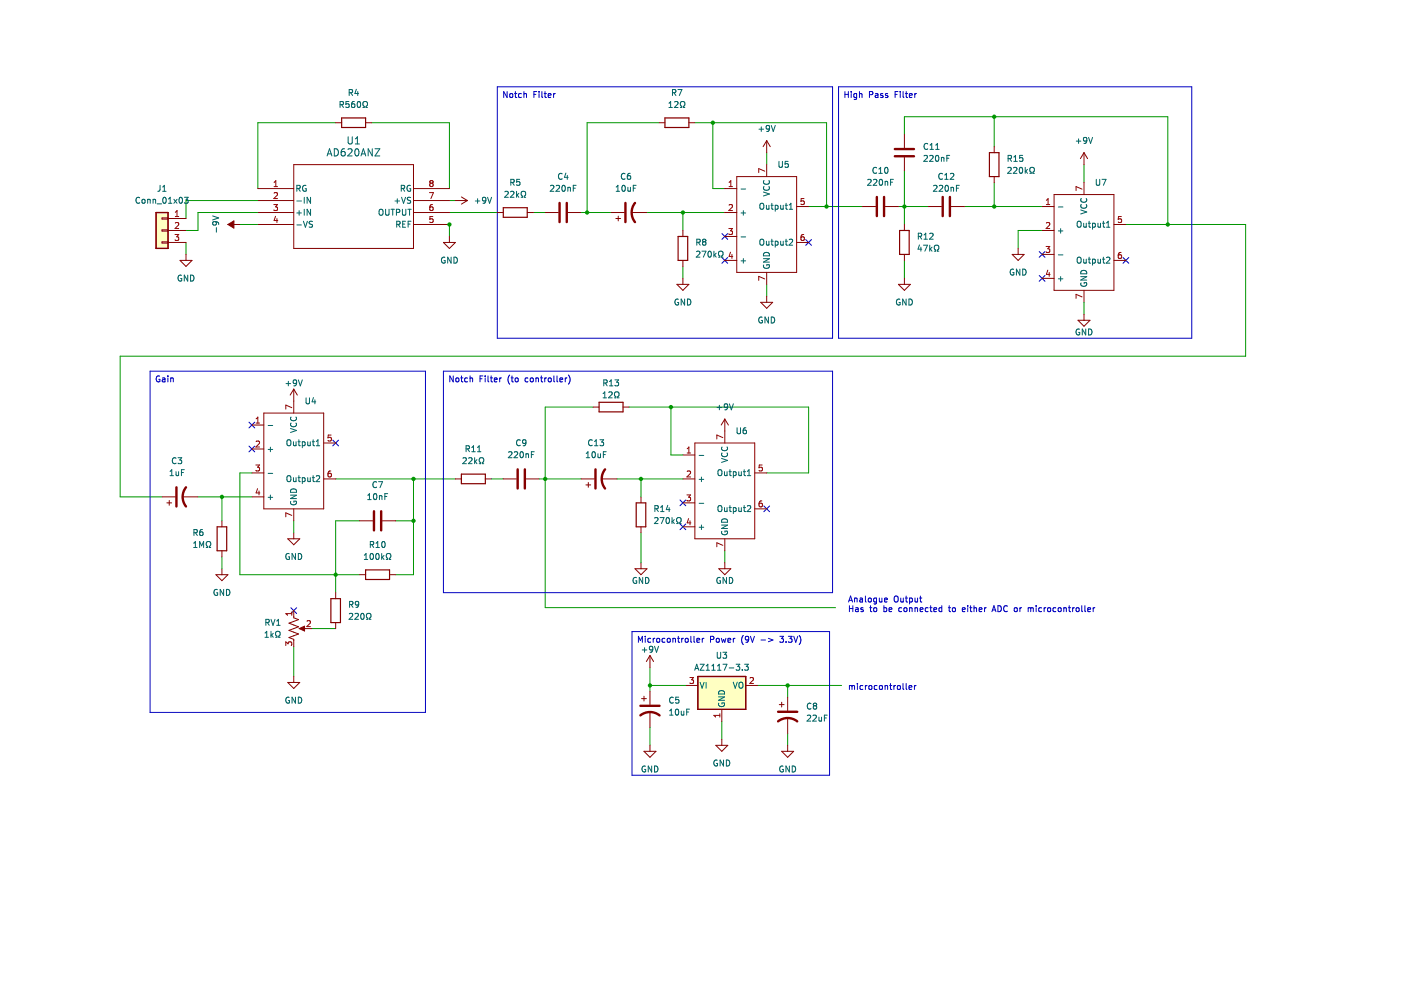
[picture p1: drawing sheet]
<svg xmlns="http://www.w3.org/2000/svg" width="297mm" height="210mm" viewBox="0 0 297 210" stroke-linecap="round" stroke-linejoin="round" font-family="sans-serif">
<path d="M148 143.4h10.1v7h-10.1z" fill-rule="evenodd" fill="#ffffc2"/>
<path d="M148 143.4h10.1v7h-10.1z" fill="none" stroke="#840000" stroke-width=".25"/>
<path d="M33.1 45.1h2.5v7.6h-2.5z" fill-rule="evenodd" fill="#ffffc2"/>
<path d="M141 25h5.1v2h-5.1zM33.1 45.1h2.5v7.6h-2.5zM106.7 44h5.1v2.1h-5.1zM143.8 50.1h2v5.1h-2zM127 85.3h5.1v2h-5.1zM46 111.7h2.1v5.1h-2.1zM134.9 106.6h2v5.1h-2zM70.2 126.9h2v5.1h-2zM77.5 120.8h5.1v2.1h-5.1zM148 143.4h10.1v7h-10.1z" fill="none" stroke="#840000" stroke-width=".25"/>
<g fill="none" stroke="#000084" stroke-width=".21">
<path d="M153.1 54.6l1.2 1.2M153.1 49.5l1.2 1.2M154.3 54.6l-1.2 1.2M154.3 49.5l-1.2 1.2M170.8 50.8l1.3 1.2M172.1 50.8l-1.3 1.2M220.3 53.3l1.3 1.3M220.3 58.4l1.3 1.2M221.6 53.3l-1.3 1.3M221.6 58.4l-1.3 1.2M238.1 54.6l1.2 1.2M239.3 54.6l-1.2 1.2"/>
<path d="M52.8 89.5l1.2 1.2M52.8 94.6l1.2 1.2M54 89.5l-1.2 1.2M54 94.6l-1.2 1.2M70.6 93.3l1.2 1.2M71.8 93.3l-1.2 1.2M144.2 106l1.2 1.2M144.2 111.1l1.2 1.2M145.4 106l-1.2 1.2M145.4 111.1l-1.2 1.2M161.9 107.3l1.3 1.2M163.2 107.3l-1.3 1.2"/>
<path d="M61.7 128.9l1.2 1.2M62.9 128.9l-1.2 1.2"/>
</g>
<g fill="none" stroke="#009600" stroke-width=".21">
<path d="M71.2 26h-16.5v14M78.8 26h16.5v14M139.7 26h-15.2v19.1M147.3 26h27.9v17.8M151.1 26v14h2.6M162.6 32.4v2.5M191.7 28.6v-3.8h55.9v22.8M191.7 36.2v11.4M210.8 24.8v6.3M210.8 38.7v5.1M229.8 34.9v3.8M39.4 51.4v2.5"/>
<path d="M50.9 47.6h3.8M54.7 45.1h-12.7v3.8h-2.6M54.7 42.5h-15.3v3.8M90.2 47.6h5.1v2.5M95.3 45.1h10.1M95.3 42.5h1.3M113.1 45.1h2.5M123.2 45.1h6.4M137.2 45.1h16.5M144.8 45.1v3.8M144.8 56.5v2.5M171.4 43.8h11.5"/>
<path d="M190.5 43.8h6.3M191.7 55.2v3.8M204.4 43.8h16.5M220.9 48.9h-5v3.8M238.7 47.6h25.4v27.9h-238.6v29.9h8.9M162.6 60.3v2.5M229.8 64.1v2.5M125.7 86.3h-10.1v42.5h61.6M133.4 86.3h38v14h-8.8M142.2 86.3v10.2h2.6M42 105.4h11.4M47.1 105.4v5"/>
<path d="M47.1 118v2.6M53.4 100.3h-2.5v21.6h25.3M62.3 110.4v2.6M71.2 101.5h25.4M76.2 110.4h-5v15.3M83.9 110.4h3.8M87.7 101.5v20.4h-3.8M104.2 101.5h2.5M114.3 101.5h8.9M130.8 101.5h14M135.9 101.5v3.9M135.9 113v6.3"/>
<path d="M153.7 116.8v2.5M62.3 137.1v6.3M66.1 133.3h5.1M137.8 145.3h7.6M137.8 141.5v5.1M137.8 154.2v3.8M153 152.9v3.9M160.7 145.3h17.7M167 145.3v2.6M167 155.5v2.5"/>
</g>
<g fill="none" stroke="#0000c2" stroke-width=".21">
<path d="M105.4 18.4h71.1v53.3h-71.1zM107.5 19.4v1.3l-.7-1.3v1.3M108.1 20l.2-.2 .4 .2-.1 .6h-.5zM109.1 19.8h.5M109.3 19.4v1.1l.3 .2M110.5 19.9l-.3-.1-.3 .3 .2 .5h.4M111.1 20l.5-.1v.8M111.1 19.4v1.3M113.8 19.4h-.6v1.3M114.3 19.4v.1M114.3 19.8v.9M114.9 19.4v1.1l.2 .2"/>
<path d="M115.4 19.8h.5M115.6 19.4v1.1l.3 .2M117.4 19.8v.9M117.7 19.8l-.3 .3M177.8 18.4h74.9v53.3h-74.9zM179.1 19.4v1.3M179.9 19.4v1.3M180.5 19.4v.1M180.5 19.8v.9M181.6 19.9l-.3-.1-.3 .3 .1 .5h.5M181.6 19.8v1.1l-.2 .2-.3-.1M182.2 20l.5-.1 .1 .8"/>
<path d="M182.2 19.4v1.3M185.6 19.9h.5l.1 .8M187.2 19.9l-.3-.1-.2 .2 .1 .2 .4 .1v.3h-.5M188.2 19.9l-.3-.1-.2 .2 .1 .2 .4 .1v.3h-.5M190.4 19.4h-.6v1.3M190.9 19.4v.1M190.9 19.8v.9M191.5 19.4v1.1l.2 .2M192 19.8h.4M192.1 19.4v1.1l.3 .2M194 19.8v.9M194.3 19.8l-.3 .3"/>
<path d="M113.2 20h.4M116.2 20.3l.6-.2v-.2l-.4-.1-.2 .2 .1 .6h.5M179.1 20h.8M184.3 20.1l.6-.1 .1-.5-.7-.1v1.3M186.2 20.1l-.7 .3 .2 .3 .5-.1M189.8 20h.4M192.8 20.3l.6-.2-.1-.2-.3-.1-.2 .2 .1 .6h.4M31.8 78.7h58.4v72.3h-58.4zM33.8 79.8a.58 .58 0 0 0-.7 .5 .58 .58 0 0 0 .8 .5v-.4h-.2M35.6 79.7v.1M94 78.7h82.5v47h-82.5zM96.1 79.7v1.3l-.7-1.3v1.3"/>
<path d="M97.8 79.7v1.1l.3 .2M99.7 79.7v1.3M102.4 79.7h-.6v1.3M102.9 79.7v.1M103.5 79.7v1.1l.1 .2M104.1 79.7v1.1l.3 .2M108.1 79.5a1.46 1.46 0 0 0 0 2M108.5 79.7v1.1l.3 .2M114.8 79.7v1.1l.3 .2M117.4 79.7v1.1l.2 .2M118.1 79.7v1.1l.2 .2M120.5 79.5a1.46 1.46 0 0 1 0 2"/>
<path d="M34.4 80.2h.5l.1 .8M35 80.4l-.6 .3 .2 .3 .4-.1M35.6 80.1v.9M36.2 80.2h.5v.8M36.2 80.1v.9M96.7 80.2l.2-.1 .3 .1v.7l-.5-.1zM97.7 80.1h.4M99.1 80.2l-.3-.1-.3 .3 .1 .5h.5M99.7 80.2h.4l.1 .8M101.8 80.3h.4M102.9 80.1v.9M104 80.1h.4"/>
<path d="M104.8 80.5l.6-.1-.1-.2-.3-.1-.2 .2 .1 .6h.4M105.9 80.1v.9M106.3 80.1l-.4 .3M108.4 80.1h.4M109.3 80.2l.2-.1 .3 .1v.7l-.5-.1zM111.9 80.2l-.3-.1-.3 .3 .1 .5h.5M112.5 80.2l.2-.1 .3 .1v.7l-.5-.1zM113.6 80.2h.5l.1 .8M113.6 80.1v.9M114.6 80.1h.5M115.5 80.1v.9M115.9 80.1l-.4 .3"/>
<path d="M116.3 80.2l.2-.1 .3 .1v.7l-.5-.1zM118.7 80.5l.6-.1-.1-.2-.3-.1-.2 .2 .1 .6h.4M119.8 80.1v.9M120.2 80.1l-.4 .3M134 133.9h41.9v30.5h-41.9zM135.4 136.2v-1.3l.4 .9 .4-.9v1.3M136.8 134.9v.1M136.8 135.3v.9M138 135.4l-.4-.1-.3 .3 .2 .5h.5M138.5 135.3v.9M138.9 135.3l-.4 .3M139.3 135.5l.2-.2 .3 .2v.6h-.5z"/>
<path d="M141 135.4l-.4-.1-.2 .3 .1 .5h.5M141.5 135.5l.2-.2 .4 .2-.1 .6h-.5zM142.7 135.5l.4-.1 .1 .8M142.7 135.3v.9M143.6 135.3h.5M143.8 134.9v1.1l.3 .2M144.5 135.3v.9M144.9 135.3l-.4 .3M145.3 135.5l.2-.2 .4 .2-.1 .6h-.5zM146.5 134.9v1.1l.2 .2M147.1 134.9v1.1l.2 .2M147.7 135.8l.6-.2v-.2l-.4-.1-.2 .2 .1 .6h.5"/>
<path d="M148.9 135.3v.9M149.3 135.3l-.4 .3M150.6 135.6l.6-.1 .1-.5-.7-.1v1.3M151.9 135.5l.2-.2 .4 .2-.1 .6h-.5zM152.9 135.3l.3 .9 .2-.6 .3 .6 .2-.9M154.3 135.8l.6-.2v-.2l-.4-.1-.2 .2 .1 .6h.5M155.5 135.3v.9M155.8 135.3l-.3 .3M157.6 134.7a1.46 1.46 0 0 0 0 2M158.7 135.5l-.2 .2-.4-.1v-.6l.4-.1 .2 .3v.7l-.2 .2-.4 .1M159.1 134.9l.4 1.3 .5-1.3M161.3 135.7h1"/>
<path d="M162.9 135.3l1 .4-1 .4M165.3 134.9h.8l-.4 .5 .4 .1v.6l-.2 .1-.6-.1M166.7 136.1v.1M167.1 134.9h.8l-.4 .5 .4 .1v.6l-.2 .1-.6-.1M168.3 134.9l.4 1.3 .4-1.3M169.4 134.7a1.46 1.46 0 0 1 0 2M179.9 127.6l.4-1.2 .5 1.2M180 127.3h.6M180.1 128.4v1.3M180.1 129h.7M180.8 128.4v1.3M181.2 126.8v.8"/>
<path d="M181.2 126.9h.5v.7M181.4 128.9h.5l.1 .8M182 129.1l-.6 .3 .1 .3 .5-.1M182.3 126.9h.5l.1 .7M182.9 127.1l-.6 .2 .2 .3h.4M183 128.9l-.3-.1-.2 .2 .1 .2 .4 .1v.3h-.5M183.5 126.4v1.1l.2 .1M184.1 126.9l.2-.1 .4 .1-.1 .7-.5-.1zM184.4 128.8h.5M184.6 128.4v1.1l.3 .2M185.3 129l.2-.2 .3 .2v.6h-.5zM185.8 126.9l-.3-.1-.3 .2 .2 .6h.4"/>
<path d="M185.8 126.8v1l-.2 .3-.3-.1M186.4 126.8l.1 .8 .5-.1M187 126.8v.8M187.4 128.9l.4-.1 .2 .3-.1 .5h-.5M187.4 128.4v1.3M187.5 127.2l.6-.1v-.2l-.4-.1-.2 .2 .1 .6h.5M188.5 129.3l.6-.2-.1-.2-.3-.1-.2 .2 .1 .6h.4M189.6 126.6l.3-.2a.43 .43 0 0 1 .5 .4v.4a.42 .42 0 0 1-.4 .5 .42 .42 0 0 1-.4-.5zM191 126.8v.8l.5-.1M191.2 128.9l-.4-.1-.2 .3 .1 .5h.5M191.5 126.8v.8M191.7 129l.2-.2 .3 .2v.6h-.5z"/>
<path d="M191.9 126.8h.5M192.1 126.4v1.1l.3 .1M192.8 126.9l.4-.1 .3 .2-.2 .6h-.5M192.8 126.8v1.3M192.8 129l.5-.1 .1 .8M192.8 128.8v.9M194 126.8l.1 .8 .4-.1M194 129l.5-.1v.8M194 128.8v.9M194.5 126.8v.8M195 126.8h.4M195.1 129.3l.6-.2-.1-.2-.3-.1-.2 .2v.6h.5"/>
<path d="M195.1 126.4v1.1l.3 .1M196.8 128.9l-.4-.1-.2 .3 .1 .5h.5M197.1 128.8h.5M197.3 128.4v1.1l.3 .2M198 129.3l.6-.2-.1-.2-.3-.1-.2 .2v.6h.5M199.7 128.9l-.4-.1-.2 .3 .1 .5h.5M199.7 128.4v1.3M201.1 128.8h.5M201.2 128.4v1.1l.4 .2M202 129l.2-.2 .3 .2v.6h-.5zM204 129.3l.6-.2v-.2l-.4-.1-.2 .2 .1 .6h.5M205.2 128.4v.1"/>
<path d="M205.2 128.8v.9M205.6 128.8h.5M205.8 128.4v1.1l.3 .2M206.5 129l.5-.1 .1 .8M206.5 128.4v1.3M207.6 129.3l.6-.2-.1-.2-.3-.1-.2 .2 .1 .6h.4M208.7 128.8v.9M209.1 128.8l-.4 .3M210.3 129.7l.4-1.3 .5 1.3M210.4 129.3h.6M211.6 128.4a.64 .64 0 0 1 .7 .7 .64 .64 0 0 1-.7 .6zM213.6 128.5a.56 .56 0 0 0-.8 .6 .56 .56 0 0 0 .8 .5"/>
<path d="M215.1 129l.2-.2 .3 .2v.6h-.5zM216.2 128.8v.9M216.6 128.8l-.4 .3M218 129l.4-.2 .1 .2M218 128.8v.9M218.5 129l.2-.2 .3 .1 .1 .8M218.5 129v.7M219.7 128.4v.1M219.7 128.8v.9M220.8 128.9l-.3-.1-.3 .3 .1 .5h.5M221.4 128.8v.9M221.7 128.8l-.3 .3"/>
<path d="M222.2 129l.1-.2 .4 .2-.1 .6h-.4zM223.9 128.9l-.4-.1-.3 .3 .2 .5h.5M224.4 129l.2-.2 .3 .2v.6h-.5zM225.5 129l.5-.1 .1 .8M225.5 128.8v.9M226.5 128.8h.5M226.7 128.4v1.1l.3 .2M227.4 128.8v.9M227.8 128.8l-.4 .3M228.2 129l.2-.2 .3 .2v.6h-.5zM229.4 128.4v1.1l.1 .2M230 128.4v1.1l.2 .2"/>
<path d="M230.6 129.3l.6-.2v-.2l-.4-.1-.2 .2 .1 .6h.5M231.8 128.8v.9M232.1 128.8l-.3 .3M180.1 145.3v.9M180.1 145.5l.4-.2 .1 .2M180.6 145.5l.2-.2 .3 .1 .1 .8M180.6 145.5v.7M181.8 144.9v.1M181.8 145.3v.9M182.9 145.4l-.3-.1-.3 .3 .2 .5h.4M183.5 145.3v.9M183.8 145.3l-.3 .3"/>
<path d="M184.3 145.5l.1-.2 .4 .2-.1 .6h-.4zM186 145.4l-.4-.1-.2 .3 .1 .5h.5M186.5 145.5l.2-.2 .3 .2v.6h-.5zM187.6 145.5l.5-.1 .1 .8M187.6 145.3v.9M188.6 145.3h.5M188.8 144.9v1.1l.3 .2M189.5 145.3v.9M189.9 145.3l-.4 .3M190.4 145.4l.3-.1 .2 .3v.3l-.2 .3-.5-.3zM191.5 144.9v1.1l.1 .2M192.1 144.9v1.1l.2 .2"/>
<path d="M192.7 145.8l.6-.2v-.2l-.4-.1-.2 .2 .1 .6h.5M193.9 145.3v.9M194.2 145.3l-.3 .3"/>
</g>
<g fill="none" stroke="#840000" stroke-width=".21">
<path d="M139.7 26h1.3M146.1 26h1.2M153.7 40h2.5M156.2 37.4h12.7v20.4h-12.7zM162.6 29.8v2.6M162.6 34.9v2.5M162.6 29.8l-.8 1.3M162.6 29.8l.7 1.3M105.4 45.1h1.3M111.8 45.1h1.3M115.6 45.1h2.8M120.4 45.1h2.8"/>
<path d="M129.6 45.1h2.7M130.6 46.3h1M131.1 45.8v1M133.9 45.1h3.3M144.8 48.9v1.2M144.8 55.2v1.3M144.8 59v1.3M153.7 45.1h2.5M153.7 50.1h2.5M153.7 55.2h2.5M162.6 57.8v2.5M168.9 43.8h2.5"/>
<path d="M168.9 51.4h2.5M143.5 60.3h2.6l-1.3 1.3zM161.3 64.1h2.5l-1.2 1.3zM162.6 62.8v1.3M53.4 90.1h2.5M53.4 95.2h2.5M55.9 87.6h12.7v20.3h-12.7zM62.3 82.5v5.1M62.3 82.5l-.8 1.3M62.3 82.5l.7 1.3M68.6 93.9h2.6M125.7 86.3h1.3"/>
<path d="M132.1 86.3h1.3M153.7 88.8v2.6M153.7 88.8l-.8 1.3M153.7 88.8l.7 1.3M34.4 105.4h2.8M35.4 106.6h1M35.9 106.1v1M38.7 105.4h3.3M47.1 110.4v1.3M47.1 116.8v1.2M53.4 100.3h2.5M53.4 105.4h2.5"/>
<path d="M61 114.2h2.6l-1.3 1.3zM62.3 107.9v2.5M62.3 113v1.2M68.6 101.5h2.6M76.2 110.4h2.8M81.1 110.4h2.8M106.7 101.5h2.8M111.5 101.5h2.8M123.2 101.5h2.8M124.2 102.8h1M124.7 102.3v1M127.5 101.5h3.3"/>
<path d="M135.9 105.4v1.2M135.9 111.7v1.3M135.9 119.3v1.3M153.7 119.3v1.3M45.8 121.9h2.5l-1.2 1.2zM47.1 120.6v1.3M62.3 130.7v.3M62.3 135.6v.2M63.8 133.3h1M71.2 125.7v1.2M71.2 132v1.3M76.2 121.9h1.3"/>
<path d="M82.6 121.9h1.3M134.6 120.6h2.6l-1.3 1.3zM137.8 139v2.5M137.8 139l-.8 1.3M137.8 139l.8 1.3M152.4 120.6h2.5l-1.2 1.3zM61 144.7h2.6l-1.3 1.3zM62.3 143.4v1.3M136 148.1h1M136.5 159.3h2.6l-1.3 1.3zM136.5 147.6v1M137.8 146.6v2.8"/>
<path d="M137.8 150.9v3.3M137.8 158v1.3M145.4 145.3h2.6M151.8 158h2.5l-1.3 1.3zM153 150.4v2.5M153 156.8v1.2M158.1 145.3h2.6M165.2 149.4h1M165.7 148.9v1M165.7 159.3h2.6l-1.3 1.3zM167 147.9v2.8M167 152.2v3.3"/>
<path d="M167 158v1.3"/>
</g>
<g fill="none" stroke="#006464" stroke-width=".21">
<path d="M142.6 19.6h.6v-.5l-.6-.1v1.3M142.9 19.6l.4 .7M143.7 19h.9l-.6 1.3M108.3 38.7l.6-.1 .1-.5-.7-.1v1.3M108.6 38.7l.4 .6M110.2 38h-.6l-.1 .6h.6l.1 .6-.2 .1-.5-.1M116.7 39.4l.5-.1 .2 .4-.7 .9h.7M117.9 39.4l.5-.1 .2 .4-.7 .9h.7M119.2 36.9a.56 .56 0 0 0-.8 .5 .56 .56 0 0 0 .8 .5M119.3 39.4l.1-.1a.68 .68 0 0 1 .5 .6 .68 .68 0 0 1-.5 .7 .84 .84 0 0 1-.1-1.2zM120 36.7l-.3 .9h.8M120.3 37.2v.8"/>
<path d="M120.4 39.7v.9M120.4 39.8h.5v.8M121.5 39.9h.5M122.2 39.3h-.7v1.3M130.6 39.7l.4-.4v1.3M132 39.4l.2-.1a.68 .68 0 0 1 .4 .6 .68 .68 0 0 1-.4 .7l-.3-.5zM132.5 36.9a.56 .56 0 0 0-.8 .5 .56 .56 0 0 0 .8 .5M133.1 39.7l.1 .8 .5-.1M133.6 36.8h-.4l-.1 .3-.1 .7 .2 .2 .5-.1-.1-.6-.4-.1-.2 .3M133.7 39.7v.9M134.3 39.9h.4M134.9 39.3h-.6v1.3"/>
<path d="M141.8 22.8h.8M141.8 21.9l.4-.4v1.3M143 21.6l.5-.1 .3 .4-.8 .9h.8M144.2 22.8h.3v-.3a.54 .54 0 0 1-.2-.7 .54 .54 0 0 1 .7-.2l.2 .6-.3 .3v.3h.3M160.9 27.4h1M161.4 26.9v1M162 38.3a.56 .56 0 0 0 .5 .8 .56 .56 0 0 0 .5-.8M162 39.6a.56 .56 0 0 0 .5 .8 .56 .56 0 0 0 .5-.8M163.2 27.1l-.3 .3-.3-.1-.1-.6 .4-.1 .3 .2-.1 .8-.2 .2-.3 .1M163.5 26.6l.4 1.3 .5-1.3M165.2 34.2v1l.2 .3 .4-.1 .1-.2v-1M167.1 34.2h-.6l-.1 .6h.6l.1 .6-.2 .1-.5-.1"/>
<path d="M107 40.7l.5-.1 .3 .3-.8 .9h.8M108.2 40.7l.5-.1 .3 .3-.8 .9h.8M109.5 40.6v1.2M109.6 41.3l.4 .5M110 41l-.5 .5M110.5 41.8h.3v-.2a.54 .54 0 0 1-.3-.8 .54 .54 0 0 1 .8-.2l.2 .6-.3 .4v.2h.3M130.6 40.6h.8M147.7 53.4l.5-.1 .2 .3-.8 .9h.8M147.7 51.4l.6-.1 .1-.5-.7-.1v1.3M148 51.4l.5 .6M148.8 53.3h.9l-.6 1.2M149.2 51.3l-.3-.3 .3-.3h.2l.3 .3-.3 .3"/>
<path d="M149.2 51.3l-.3 .2 .1 .4 .2 .1 .4-.1 .1-.2v-.2l-.3-.2M149.2 51.3h.2M150.2 53.4l.2-.1a.68 .68 0 0 1 .4 .6 .68 .68 0 0 1-.4 .6l-.3-.5zM151.4 53.3v1.2M151.5 54l.3 .5M151.8 53.7l-.4 .5M152.3 54.5h.3v-.2a.54 .54 0 0 1-.2-.8 .54 .54 0 0 1 .7-.2l.2 .6-.3 .4v.2h.3M157.1 40.1h1M157.1 45.2h1M157.1 50.2h1M157.1 55.3h1M157.6 44.7v.9"/>
<path d="M157.6 54.8v1M161.2 43.3l.2-.2a.43 .43 0 0 1 .5 .4v.4a.42 .42 0 0 1-.4 .5 .42 .42 0 0 1-.4-.5zM161.2 50.9l.2-.2a.43 .43 0 0 1 .5 .4v.5a.42 .42 0 0 1-.4 .4 .42 .42 0 0 1-.4-.4zM161.9 54.8h1.2l-1.2 .8h1.2M161.9 40.7l1.2 .4-1.2 .5M161.9 56.2a.58 .58 0 0 0 .6 .7 .58 .58 0 0 0 .5-.8h-.4v.3M161.9 53.8a.68 .68 0 0 1 .8-.2 .68 .68 0 0 1 .4 .6h-1.2zM162.5 43.5l.1 .8 .4-.1M162.5 51.1l.1 .8h.4M163 43.5v.9M163 51.1v.9M163.5 43.5h.4"/>
<path d="M163.5 51.1h.4M163.6 43.1v1.1l.3 .2M163.6 50.7v1.1l.3 .2M164.4 43.6l.3-.1 .3 .3-.2 .5h-.4M164.4 43.5v1.3M164.4 51.1v1.3M164.4 51.2l.3-.1 .3 .3-.2 .5h-.4M165.5 43.5l.1 .8 .5-.1M165.5 51.1l.1 .8h.5M166.1 43.5v.9M166.1 51.1v.9M166.5 43.5h.5"/>
<path d="M166.5 51.1h.5M166.7 43.1v1.1l.3 .2M166.7 50.7v1.1l.3 .2M167.3 43.5l.4-.4v1.3M167.3 44.4h.8M167.3 50.8l.5-.1 .3 .4-.8 .9h.8M143.8 63.5a.58 .58 0 0 0-.7 .6 .58 .58 0 0 0 .8 .5v-.5h-.3M145.1 63.4v1.3l-.7-1.3v1.3M145.8 63.4a.64 .64 0 0 1 .7 .6 .64 .64 0 0 1-.7 .7zM161.6 67.3a.58 .58 0 0 0-.7 .6 .58 .58 0 0 0 .7 .5v-.5h-.2M162.9 67.2v1.3l-.7-1.3v1.3M163.5 67.2a.64 .64 0 0 1 .8 .7 .64 .64 0 0 1-.8 .6z"/>
<path d="M36.1 99.9l.3-.3v1.3M37.3 97.2a.56 .56 0 0 0-.8 .5 .56 .56 0 0 0 .8 .5M37.7 97h.8l-.4 .5 .4 .1v.6l-.2 .1-.6-.1M39.1 99.6h-.6v1.3M56.8 90.2h1M56.8 95.3h1M57.3 94.8v1M60.7 81.3h.9M60.9 93.4l.2-.2a.43 .43 0 0 1 .6 .5v.4a.42 .42 0 0 1-.4 .4 .42 .42 0 0 1-.5-.4zM61.1 80.8v1M61.6 90.8l1.3 .5-1.3 .4M61.7 88.4a.56 .56 0 0 0 .5 .8 .56 .56 0 0 0 .5-.8"/>
<path d="M61.7 89.7a.56 .56 0 0 0 .5 .8 .56 .56 0 0 0 .5-.8M62.2 93.7l.1 .7h.5M62.8 93.7v.8M62.9 81.1l-.3 .2h-.3l-.1-.6 .4-.2 .3 .3-.1 .7-.2 .3h-.3M63.2 93.7h.5M63.2 80.5l.5 1.3 .4-1.3M63.4 93.2v1.1l.3 .2M64.1 93.7h.4l.2 .2-.1 .5h-.5M64.1 93.7v1.2M64.9 84.4v1l.2 .2h.4l.1-.2v-1M65.2 93.7l.1 .7h.5M65.8 93.7v.8"/>
<path d="M66.2 93.7h.5M66.4 93.2v1.1l.3 .2M66.5 84.3l-.3 .9h.7M66.8 84.8v.8M67.1 94.5h.7M67.1 93.6l.3-.4v1.3M107.8 95.9l.5-.1 .3 .3-.8 .9h.8M109 95.9l.5-.1 .3 .3-.8 .9h.8M110.3 93.4a.56 .56 0 0 0-.8 .5 .56 .56 0 0 0 .8 .5M110.4 95.9l.1-.1a.68 .68 0 0 1 .5 .6 .68 .68 0 0 1-.5 .6l-.3-.4zM111.5 96.3h.5l.1 .7M111.5 96.2v.8"/>
<path d="M111.5 93.8l-.2 .2h-.4l-.1-.6 .5-.2 .2 .3v.7l-.2 .2-.4 .1M112.7 96.4h.4M113.3 95.8h-.6v1.2M124.3 97h.7M124.3 96.1l.4-.3v1.2M125.6 93.4a.56 .56 0 0 0-.8 .5 .56 .56 0 0 0 .8 .5M125.6 95.9l.2-.1a.68 .68 0 0 1 .4 .6 .68 .68 0 0 1-.4 .6l-.3-.4zM126 94.5h.8M126 93.6l.4-.4v1.3M126.8 96.2v.8l.5-.1M127.2 93.2h.8l-.4 .5 .3 .1v.6l-.2 .1-.5-.1M127.3 96.2v.8"/>
<path d="M127.9 84.4h.7M127.9 83.4l.3-.3v1.3M127.9 96.4h.4M128 81.2l.6-.1 .1-.4-.7-.2v1.3M128.3 81.2l.4 .6M128.5 95.8h-.6v1.2M129.1 83.2l.5-.1 .2 .3-.8 1h.8M129.2 81.8h.7M129.2 80.9l.4-.4v1.3M130.3 84.4h.3v-.3a.54 .54 0 0 1-.3-.7 .54 .54 0 0 1 .8-.3l.1 .6-.3 .4v.3h.3M130.4 80.5h.8l-.5 .5 .4 .1v.6l-.2 .1-.5-.1M152 86.4h1"/>
<path d="M152.5 85.9v1M154.3 86.2l-.3 .2-.3-.1-.1-.6 .4-.1 .3 .3-.1 .7-.2 .2-.3 .1M154.6 85.6l.5 1.3 .4-1.3M36.1 100.9h.7M37.3 100l.1 .8 .5-.1M37.9 100v.9M38.5 100.2h.4M41.1 116.1h.7M41.1 115.2l.3-.4v1.3M41.1 112.9h.6l.1-.5-.7-.1v1.2M41.4 112.9l.4 .6M42.3 116.1v-1.3l.5 .9 .4-.9v1.3"/>
<path d="M42.9 112.3h-.3l-.2 .3-.1 .7 .3 .2 .4-.1-.1-.6h-.3l-.3 .2M43.7 116.1h.3v-.3a.54 .54 0 0 1-.3-.7 .54 .54 0 0 1 .8-.2l.2 .6-.3 .3v.3h.3M56.8 100.4h1M56.8 105.4h1M57.3 105v.9M60.9 101l.2-.1a.43 .43 0 0 1 .6 .4v.4a.42 .42 0 0 1-.4 .4 .42 .42 0 0 1-.5-.4zM61.3 117.4a.58 .58 0 0 0-.7 .6 .58 .58 0 0 0 .8 .5v-.4h-.3M61.6 105h1.3l-1.3 .7h1.3M61.7 103.9a.68 .68 0 0 1 .7-.2 .68 .68 0 0 1 .5 .7h-1.3zM61.7 106.3a.58 .58 0 0 0 .5 .7 .58 .58 0 0 0 .5-.7h-.4v.2M62.2 101.3l.1 .8 .5-.1M62.6 117.4v1.2l-.7-1.2v1.2"/>
<path d="M62.8 101.3v.8M63.2 101.3h.5M63.2 117.4a.64 .64 0 0 1 .8 .6 .64 .64 0 0 1-.8 .6zM63.4 100.9v1l.3 .2M64.1 101.3v1.2M64.1 101.3h.4l.2 .2-.1 .6h-.5M65.2 101.3l.1 .8 .5-.1M65.8 101.3v.8M66.2 101.3h.5M66.4 100.9v1l.3 .2M67.1 101l.4-.1 .3 .3-.8 .9h.8M77.2 118.6h.8"/>
<path d="M77.2 117.7l.4-.3v1.2M78 105.9h.7M78 105l.3-.3v1.2M78.5 115.5l.6-.1 .1-.5-.7-.1v1.3M78.6 117.5l.2-.1a.68 .68 0 0 1 .4 .6 .68 .68 0 0 1-.4 .6l-.3-.5zM78.8 115.5l.4 .6M79.3 104.8l.2-.1a.68 .68 0 0 1 .4 .6 .68 .68 0 0 1-.4 .6l-.3-.5zM79.7 116.1h.7M79.7 115.2l.4-.4v1.3M79.8 117.5l.2-.1a.68 .68 0 0 1 .4 .6 .68 .68 0 0 1-.4 .6l-.3-.5zM79.8 102.2a.56 .56 0 0 0-.8 .6 .56 .56 0 0 0 .8 .5M80.3 102.1h.8l-.5 1.3"/>
<path d="M80.4 105.1v.8M80.4 105.2l.5-.1 .1 .8M80.9 117.4v1.2M81.1 114.9l.1-.1a.68 .68 0 0 1 .5 .6 .68 .68 0 0 1-.5 .7l-.3-.5zM81.1 118.1l.3 .5M81.4 117.8l-.5 .5M81.6 105.3h.4M81.9 118.6h.3v-.2a.54 .54 0 0 1-.3-.8 .54 .54 0 0 1 .8-.2l.2 .6-.3 .4v.2h.3M82.2 104.7h-.6v1.2M138.8 109.9l.5-.2 .2 .4-.8 .9h.8M138.9 107.9l.6-.1v-.5l-.6-.1v1.3M139.2 107.9l.4 .6"/>
<path d="M139.9 109.7h.9l-.6 1.3M140.1 108.5h.7M140.1 107.6l.3-.4v1.3M141.4 109.8l.1-.1a.68 .68 0 0 1 .5 .7 .68 .68 0 0 1-.5 .6 .84 .84 0 0 1-.1-1.2zM141.6 107.1l-.3 .9h.8M141.9 107.6v.9M142.5 109.7v1.3M142.6 110.5l.4 .5M143 110.2l-.5 .4M143.4 111h.3v-.2a.54 .54 0 0 1-.2-.8 .54 .54 0 0 1 .7-.2l.2 .6-.3 .4v.2h.3M46.1 125a.58 .58 0 0 0-.8 .6 .58 .58 0 0 0 .8 .5v-.4h-.2M47.4 125v1.2l-.7-1.2v1.2"/>
<path d="M48 125a.64 .64 0 0 1 .8 .6 .64 .64 0 0 1-.8 .6zM74.1 130.2l.4-.2 .3 .4-.8 .9h.8M74.1 128.2l.6-.1 .1-.5-.7-.1v1.3M74.4 128.2l.4 .6M75.3 130.2l.5-.2 .2 .4-.8 .9h.8M76.1 128.1l-.3 .2-.4-.1v-.6l.4-.1 .3 .2-.1 .8-.2 .2-.4 .1M76.6 130.2l.2-.2a.68 .68 0 0 1 .4 .7 .68 .68 0 0 1-.4 .6l-.3-.5zM77.7 131.3h.3v-.2a.54 .54 0 0 1-.3-.8 .54 .54 0 0 1 .8-.2l.2 .6-.3 .4v.2h.3M134.9 122.5a.58 .58 0 0 0-.7 .6 .58 .58 0 0 0 .8 .5v-.4h-.2M136.2 137.8h.9M136.3 122.4v1.3l-.8-1.3v1.3M136.7 137.3v1"/>
<path d="M136.9 122.4a.64 .64 0 0 1 .7 .7 .64 .64 0 0 1-.7 .6zM138.4 137.6l-.2 .2h-.4l-.1-.7 .5-.1 .2 .3-.1 .7-.1 .2-.4 .1M138.8 137l.4 1.3 .4-1.3M152.1 138.3v1l.2 .3 .4-.1 .1-.2v-1M152.7 122.5a.58 .58 0 0 0-.7 .6 .58 .58 0 0 0 .8 .5v-.4h-.3M153.3 138.3h.8l-.5 .5 .4 .1v.5l-.2 .2-.5-.2M154 122.4v1.3l-.7-1.3v1.3M154.6 122.4a.64 .64 0 0 1 .8 .7 .64 .64 0 0 1-.8 .6zM61.3 147.9a.58 .58 0 0 0-.7 .6 .58 .58 0 0 0 .8 .5v-.5h-.3M62.6 147.8v1.3l-.7-1.3v1.3M63.2 147.8a.64 .64 0 0 1 .8 .7 .64 .64 0 0 1-.8 .6zM142 151.6h.7"/>
<path d="M142 150.7l.3-.3v1.2M142.8 147.9a.56 .56 0 0 0-.8 .6 .56 .56 0 0 0 .8 .5M143.3 150.5l.2-.1a.68 .68 0 0 1 .4 .6 .68 .68 0 0 1-.4 .6l-.3-.5zM143.9 147.8h-.6l-.1 .6h.6l.1 .6-.2 .1-.5-.1M144.4 150.8l.1 .8 .5-.1M145 150.8v.8M145.6 151h.4M146.2 150.4h-.6v1.2M147.3 142.1l.4-1.3 .4 1.3M147.4 141.7h.6M148.4 144.6l.5 1.3 .4-1.3M148.4 140.8h.9l-.9 1.3h.9"/>
<path d="M149.7 144.6v1.3M149.7 142.1h.7M149.7 141.2l.4-.4v1.3M150.9 141.2l.4-.4v1.3M150.9 142.1h.7M152.1 142.1h.8M152.1 141.2l.4-.4v1.3M152.3 147.8h1.3l-1.3 .7h1.3M152.4 149.1a.58 .58 0 0 0 .6 .7 .58 .58 0 0 0 .5-.8h-.4v.3M152.4 146.7a.68 .68 0 0 1 .8-.2 .68 .68 0 0 1 .4 .7h-1.3zM153.3 140.8h.8l-.5 1.3M154.6 141.6h1"/>
<path d="M155.5 144.6l.4 1.3 .4-1.3M156.1 140.8h.7l-.4 .5 .4 .1v.6l-.2 .1-.5-.1M156.7 144.8l.3-.2a.43 .43 0 0 1 .5 .5v.4a.42 .42 0 0 1-.4 .4 .42 .42 0 0 1-.4-.4zM157.4 142v.1M157.9 140.8h.8l-.5 .5 .4 .1v.6l-.2 .1-.5-.1M171.2 151.7l.4-.1 .3 .4-.8 .9h.8M171.9 149.2a.56 .56 0 0 0-.7 .5 .56 .56 0 0 0 .7 .5M172.4 151.7l.5-.1 .2 .4-.8 .9h.8M172.7 149.6l-.3 .3 .1 .3 .2 .2 .3-.1 .2-.2v-.2l-.3-.3M172.7 149.6l-.3-.2 .3-.3h.2l.3 .2-.3 .3M172.7 149.6h.2M173.6 152l.1 .8h.5"/>
<path d="M174.2 152v.9M174.8 152.2h.4M175.4 151.6h-.6v1.3M136.8 162.5a.58 .58 0 0 0-.7 .6 .58 .58 0 0 0 .8 .5v-.5h-.2M138.2 162.4v1.3l-.8-1.3v1.3M138.8 162.4a.64 .64 0 0 1 .7 .6 .64 .64 0 0 1-.7 .7zM152.1 161.2a.58 .58 0 0 0-.8 .6 .58 .58 0 0 0 .8 .5v-.4h-.2M153.4 161.1v1.3l-.7-1.3v1.3M154 161.1a.64 .64 0 0 1 .7 .7 .64 .64 0 0 1-.7 .6zM166 162.5a.58 .58 0 0 0-.7 .6 .58 .58 0 0 0 .8 .5v-.5h-.2M167.4 162.4v1.3l-.8-1.3v1.3M168 162.4a.64 .64 0 0 1 .7 .6 .64 .64 0 0 1-.7 .7z"/>
</g>
<g fill="none" stroke="#840000" stroke-width=".51">
<path d="M118.6 43v4.1M120.2 43v4.1M132.6 43v4.1M134.6 43a3.3 3.3 0 0 0 0 4.1M109.8 99.5v4.1M111.3 99.5v4.1M126.3 99.5v4.1M128.3 99.5a3.3 3.3 0 0 0 0 4.1M37.4 103.3v4.1M39.4 103.3a3.3 3.3 0 0 0 0 4.1M79.3 108.4v4.1M80.8 108.4v4.1"/>
<path d="M135.8 151.7a3.3 3.3 0 0 1 4 0M135.8 149.6h4M165 152.9a3.3 3.3 0 0 1 4 0M165 150.9h4"/>
</g>
<g fill="none" stroke="#a90000" stroke-width=".21">
<path d="M154.6 39.6h.7M154.6 38.7l.3-.4v1.3M162.1 36.3l-1.2-.5v.8M154.5 48.5h.8l-.4 .4 .3 .2v.5l-.1 .1-.6-.1M154.6 43.5l.5-.1 .2 .3-.8 .9h.8M154.9 53.5l-.3 .9h.8M155.2 54v.8M162.1 59.1l-1.2-.5v.8M170.4 49.7l-.3 .1-.2 .2-.1 .7 .3 .3 .4-.1-.1-.6-.3-.1-.3 .2M170.5 42.1h-.6l-.1 .6 .6-.1 .1 .7-.2 .1-.5-.1M54.2 98.6h.8l-.4 .5 .4 .1v.5l-.2 .2-.6-.2M54.3 89.7h.7"/>
<path d="M54.3 88.8l.4-.4v1.3M54.3 93.6l.5-.1 .2 .4-.8 .9h.8M61.9 86.4l-1.3-.5v.8M70.1 99.9h-.3l-.2 .3-.1 .7 .3 .2 .4-.1-.1-.6-.3-.1-.3 .3M70.2 92.2h-.6l-.1 .6h.6l.1 .6-.2 .1-.5-.1M54.6 103.6l-.3 .9h.8M54.9 104.1v.8M61.9 109.3l-1.3-.6v.9M146.3 143.6h.8l-.5 .5 .4 .2v.5l-.2 .1-.5-.1M152.6 151.3v.7M152.6 151.7h-1.2l.3 .3M159 143.8l.5-.2 .2 .4-.7 .9h.7"/>
</g>
<path d="M63.4 133.3l1.2-.5v1z" fill="#840000"/>
<g fill="none" stroke="#840000" stroke-width=".21">
<path d="M191.7 28.6v2.8M191.7 33.4v2.8M210.8 31.1v1.3M210.8 37.4v1.3M229.8 32.4v2.5M229.8 38.7v2.6M229.8 32.4l-.7 1.2M229.8 32.4l.8 1.2M38.2 55.2h2.5l-1.3 1.3zM39.4 53.9v1.3M48.3 47.6h2.6M182.9 43.8h2.8"/>
<path d="M187.7 43.8h2.8M191.7 47.6v1.3M191.7 53.9v1.3M191.7 59v1.3M196.8 43.8h2.8M201.7 43.8h2.7M214.6 53.9h2.5l-1.2 1.3zM215.9 52.7v1.2M220.9 43.8h2.6M220.9 48.9h2.6M220.9 53.9h2.6M220.9 59h2.6"/>
<path d="M223.5 41.3h12.7v20.3h-12.7zM236.2 47.6h2.5M236.2 55.2h2.5M190.5 60.3h2.5l-1.3 1.3zM228.6 67.9h2.5l-1.3 1.3zM229.8 61.6v2.5M229.8 66.6v1.3M144.8 96.5h2.5M147.3 93.9h12.7v20.3h-12.7zM153.7 91.4v2.5M96.6 101.5h1.2M102.9 101.5h1.3"/>
<path d="M144.8 101.5h2.5M144.8 106.6h2.5M144.8 111.7h2.5M153.7 114.2v2.6M160 100.3h2.6M160 107.9h2.6M62.3 131l1 .4-2 .7 2 .8-2 .8 2 .7-2 .8 1 .4M62.3 129.5v1.2M62.3 135.8v1.3M63.4 133.3l1.2-.5v1zM64.8 133.3h1.3"/>
</g>
<g fill="none" stroke="#a90000" stroke-width=".21">
<path d="M221.8 52.3h.8l-.4 .4 .3 .2v.5l-.2 .1-.5-.1M221.9 43.4h.7M221.9 42.5l.3-.4v1.3M221.9 47.3l.4-.1 .3 .3-.8 1h.8M222.2 57.3l-.3 .9h.7M222.5 57.8v.8M229.4 40.1l-1.3-.5v.8M237.7 53.5l-.4 .1-.2 .2v.8l.2 .2 .4-.1v-.6l-.4-.1-.2 .3M237.7 45.9h-.6v.6h.6v.6l-.1 .1-.5-.1M229.4 63l-1.3-.6v.9M145.7 96h.7M145.7 95.1l.4-.3v1.2"/>
<path d="M145.7 100l.5-.1 .2 .3-.8 .9h.8M153.3 92.8l-1.3-.6v.9M161.6 98.6h-.6l-.1 .6 .6-.1 .1 .6-.2 .2-.5-.2M145.6 104.9h.8l-.4 .5 .4 .1v.6l-.2 .1-.6-.1M146 110l-.3 .9h.8M146.3 110.4v.9M153.3 115.6l-1.3-.5v.8M161.5 106.2l-.3 .1-.2 .2-.1 .7 .3 .3 .4-.1-.1-.7h-.3l-.3 .2M60.6 136.9v-.8l.5 .4 .1-.4h.5l.2 .2-.2 .6M61.9 129.7v.8M61.9 130.1h-1.3l.4 .4M65.1 131.7l.5-.1 .2 .4-.8 .9h.8"/>
</g>
<g fill="none" stroke="#006464" stroke-width=".21">
<path d="M184 38.1l.5-.1 .2 .4-.8 .9h.8M185.2 38.1l.5-.1 .2 .4-.8 .9h.8M185.9 35.6a.56 .56 0 0 0-.8 .5 .56 .56 0 0 0 .8 .5M186.3 36.8h.8M186.3 35.8l.4-.3v1.3M186.5 38.1l.2-.1a.68 .68 0 0 1 .4 .7 .68 .68 0 0 1-.4 .6l-.3-.5zM187.7 38.6l.5-.1v.8M187.7 38.4v.9M187.7 35.5h.2a.68 .68 0 0 1 .4 .6 .68 .68 0 0 1-.4 .7 .84 .84 0 0 1-.2-1.3zM188.8 38.6h.4M189.4 38h-.6v1.3M195.9 33.1l.5-.2 .2 .4-.7 .9h.7"/>
<path d="M196.7 30.5a.56 .56 0 0 0-.8 .5 .56 .56 0 0 0 .8 .6M197.1 33.1l.5-.2 .2 .4-.7 .9h.7M197.2 30.8l.3-.4v1.3M197.2 31.7h.7M197.9 39.4l.5-.1 .3 .4-.8 .9h.8M198.4 31.7h.7M198.4 30.8l.4-.4v1.3M198.5 33l.1-.1a.68 .68 0 0 1 .5 .7 .68 .68 0 0 1-.5 .6 .84 .84 0 0 1-.1-1.2zM199.2 39.4l.4-.1 .3 .4-.8 .9h.8M199.6 33.4v.8M199.6 33.5l.5-.1v.8M199.8 36.9a.56 .56 0 0 0-.8 .5 .56 .56 0 0 0 .8 .5"/>
<path d="M200.3 38h.7M200.3 37.1l.4-.3v1.2M200.5 39.4l.2-.1a.68 .68 0 0 1 .4 .6 .68 .68 0 0 1-.4 .7l-.3-.5zM200.7 33.6h.5M201.4 32.9h-.7v1.3M201.5 36.9l.5-.1 .2 .3-.7 .9h.7M201.6 39.8h.5l.1 .8M201.6 39.7v.9M202.8 39.9h.4M203.4 39.3h-.6v1.3M213.7 35.6l.5-.1 .2 .3-.8 1h.8M213.7 33.6h.6l.1-.5-.7-.2v1.3"/>
<path d="M214 33.6l.5 .6M214.9 35.6l.5-.1 .2 .3-.8 1h.8M214.9 34.2h.8M214.9 33.3l.4-.4v1.3M216.3 35.5h.1a.68 .68 0 0 1 .4 .6 .68 .68 0 0 1-.4 .7 .84 .84 0 0 1-.1-1.3zM216.8 32.9h-.6v.7l.6-.1v.6l-.2 .1-.4-.1M217.4 35.5v1.3M217.5 36.3l.4 .5M217.9 35.9l-.5 .5M218.3 36.8h.3v-.3a.54 .54 0 0 1-.2-.7 .54 .54 0 0 1 .7-.3l.2 .6-.3 .4v.3h.3M228.2 29.9h1M228.7 29.4v1"/>
<path d="M230.4 29.7l-.2 .2h-.4v-.6l.4-.2 .2 .3v.7l-.2 .2-.4 .1M230.8 29.1l.4 1.3 .4-1.3M232.4 38v1.1l.3 .2 .3-.1 .2-.1v-1.1M233.6 38h.9l-.6 1.3M38.5 58.4a.58 .58 0 0 0-.8 .6 .58 .58 0 0 0 .8 .5v-.4h-.2M39.8 58.3v1.3l-.7-1.3v1.3M40.4 58.3a.64 .64 0 0 1 .7 .7 .64 .64 0 0 1-.7 .6zM194.7 50.1h.6l.1-.5-.7-.2v1.3M194.9 51.9l-.3 .9h.8M195 50.1l.4 .6M195.2 52.4v.9M195.8 52h.8l-.5 1.3"/>
<path d="M195.9 50.7h.7M195.9 49.8l.4-.4v1.3M197.1 52v1.3M197.1 49.6l.5-.2 .2 .4-.7 .9h.7M197.2 52.8l.4 .5M197.6 52.4l-.5 .5M198.1 53.3h.3v-.3a.54 .54 0 0 1-.3-.7 .54 .54 0 0 1 .8-.3l.2 .7-.3 .3v.3h.3M214.9 57.1a.58 .58 0 0 0-.7 .6 .58 .58 0 0 0 .8 .5v-.4h-.3M216.2 57.1v1.2l-.7-1.2v1.2M216.8 57.1a.64 .64 0 0 1 .8 .6 .64 .64 0 0 1-.8 .6zM224.4 43.9h1M224.4 49h1"/>
<path d="M224.4 54h1M224.4 59.1h1M224.9 48.5v.9M224.9 58.6v1M228.4 47.1l.3-.2a.43 .43 0 0 1 .5 .4v.5a.42 .42 0 0 1-.4 .4 .42 .42 0 0 1-.4-.4zM228.4 54.7l.3-.2a.43 .43 0 0 1 .5 .4v.5a.42 .42 0 0 1-.4 .4 .42 .42 0 0 1-.4-.4zM229.1 58.7h1.3l-1.3 .7h1.3M229.1 44.5l1.3 .4-1.3 .5M229.2 57.6a.68 .68 0 0 1 .8-.2 .68 .68 0 0 1 .4 .7h-1.3zM229.2 60a.58 .58 0 0 0 .6 .7 .58 .58 0 0 0 .5-.8h-.4v.3M229.3 42.1a.56 .56 0 0 0 .5 .8 .56 .56 0 0 0 .5-.8M229.3 43.4a.56 .56 0 0 0 .5 .8 .56 .56 0 0 0 .5-.8"/>
<path d="M229.8 47.3v.8h.5M229.8 54.9v.8h.5M230.3 47.3v.9M230.3 54.9v.9M230.7 47.3h.5M230.7 54.9h.5M230.9 46.9v1.1l.3 .2M230.9 54.5v1.1l.3 .2M231.6 47.4l.4-.1 .2 .3-.1 .5h-.5M231.6 47.3v1.3M231.6 54.9v1.3M231.6 55l.4-.1 .2 .3-.1 .5h-.5"/>
<path d="M232.8 47.3v.8h.5M232.8 54.9v.8h.5M233.3 47.3v.9M233.3 54.9v.9M233.8 47.3h.4M233.8 54.9h.4M233.9 46.9v1.1l.3 .2M233.9 54.5v1.1l.3 .2M234.6 48.2h.7M234.6 47.3l.4-.4v1.3M234.6 54.6l.5-.1 .2 .4-.8 .9h.8M190.8 63.5a.58 .58 0 0 0-.8 .6 .58 .58 0 0 0 .8 .5v-.5h-.2"/>
<path d="M192.1 63.4v1.3l-.7-1.3v1.3M192.7 63.4a.64 .64 0 0 1 .7 .6 .64 .64 0 0 1-.7 .7zM228.9 69.8a.58 .58 0 0 0-.8 .6 .58 .58 0 0 0 .8 .5v-.4h-.2M230.2 69.8v1.2l-.7-1.2v1.2M230.8 69.8a.64 .64 0 0 1 .7 .6 .64 .64 0 0 1-.7 .6zM98.2 97.2l.4-.2 .3 .4-.8 .9h.8M98.8 95.2l.6-.1 .1-.5-.7-.1v1.3M99.1 95.2l.4 .6M99.4 97.2l.4-.2 .3 .4-.8 .9h.8M100 95.8h.8M100 94.9l.4-.4v1.3M100.6 97v1.3"/>
<path d="M100.8 97.8l.3 .5M101.1 97.5l-.5 .5M101.2 95.8h.8M101.2 94.9l.4-.4v1.3M101.6 98.3h.3v-.2a.54 .54 0 0 1-.3-.8 .54 .54 0 0 1 .8-.2l.2 .6-.3 .4v.2h.3M148.2 96.6h1M152.3 99.8l.2-.2a.43 .43 0 0 1 .6 .4v.4a.42 .42 0 0 1-.5 .5 .42 .42 0 0 1-.4-.5zM153 97.2l1.3 .4-1.3 .4M153.1 94.8a.56 .56 0 0 0 .5 .8 .56 .56 0 0 0 .5-.8M153.1 96a.56 .56 0 0 0 .5 .8 .56 .56 0 0 0 .5-.8M154.8 99.6v1.1l.3 .2M156.3 90.7v1l.2 .3 .4-.1 .1-.2v-1"/>
<path d="M157.8 99.6v1.1l.3 .2M158.2 90.7l-.4 .1-.2 .2-.1 .7 .3 .3 .4-.2v-.6h-.4l-.3 .2M158.4 99.9l.4-.3v1.3M148.2 101.6h1M148.2 106.7h1M148.2 111.8h1M148.7 101.2v.9M148.7 111.3v1M152.4 107.3l.1-.1a.43 .43 0 0 1 .6 .4v.4a.42 .42 0 0 1-.5 .5 .42 .42 0 0 1-.4-.5zM153 111.3h1.3l-1.3 .8h1.3M153 112.7a.58 .58 0 0 0 .6 .7 .58 .58 0 0 0 .5-.8h-.4v.2M153 110.2a.68 .68 0 0 1 .8-.2 .68 .68 0 0 1 .5 .7h-1.3z"/>
<path d="M153.6 100l.1 .8 .5-.1M153.6 107.6l.1 .8 .5-.1M154.2 100v.9M154.2 107.6v.9M154.6 100h.5M154.6 107.6h.5M154.8 107.2v1.1l.3 .2M155.5 100.1l.3-.1 .3 .2-.1 .6h-.5M155.5 100v1.3M155.5 107.6v1.3M155.5 107.7l.3-.1 .3 .3-.1 .5h-.5M156.6 100l.1 .8 .5-.1"/>
<path d="M156.6 107.6l.1 .8 .5-.1M157.2 100v.9M157.2 107.6v.9M157.6 100h.5M157.6 107.6h.5M157.8 107.2v1.1l.3 .2M158.4 100.9h.8M158.4 107.3l.5-.1 .3 .4-.8 .9h.8M56.2 135.1h.7M56.2 134.2l.4-.3v1.2M56.4 132l.6-.1v-.5l-.6-.1v1.3M56.7 132l.4 .6"/>
<path d="M57.5 131.3l.4 1.3 .4-1.3M57.5 133.9v1.2M57.6 134.6l.3 .5M57.9 134.3l-.4 .5M58.4 135.1h.3v-.2a.54 .54 0 0 1-.2-.8 .54 .54 0 0 1 .7-.2l.2 .6-.3 .4v.2h.3M58.7 132.6h.7M58.7 131.7l.3-.4v1.3"/>
</g>
<path d="M209.8 32.4h2v5h-2zM190.7 48.9h2.1v5h-2.1zM97.8 100.5h5.1v2.1h-5.1z" fill="none" stroke="#840000" stroke-width=".25"/>
<path d="M189.7 31.6h4.1M189.7 33.1h4.1M185.9 41.8v4M187.4 41.8v4M199.9 41.8v4M201.4 41.8v4" fill="none" stroke="#840000" stroke-width=".51"/>
<path d="M48.3 47.6l1.3-.8v1.6z" fill="#840000"/>
<g fill="none" stroke="#840000" stroke-width=".21">
<path d="M54.7 40h7.6M62.3 34.9h25.4v17.8h-25.4zM71.2 26h1.2M77.5 26h1.3M87.7 40h7.6M34.4 46.2h1.2v.3h-1.2zM34.4 48.7h1.2v.3h-1.2zM34.4 51.3h1.2v.2h-1.2zM35.6 46.3h3.8M35.6 48.9h3.8M35.6 51.4h3.8M48.3 47.6l1.3-.8v1.6z"/>
<path d="M54.7 42.5h7.6M54.7 45.1h7.6M54.7 47.6h7.6M87.7 42.5h7.6M87.7 45.1h7.6M87.7 47.6h7.6M94 51.4h2.6l-1.3 1.3zM95.3 50.1v1.3M96.6 42.5h2.5M97.8 41.8l1.3 .7M99.1 42.5l-1.3 .8"/>
</g>
<g fill="none" stroke="#006464" stroke-width=".21">
<path d="M74 19.6h.6l.1-.5-.7-.1v1.3M74.3 19.6l.5 .7M75.5 18.9l-.3 .9h.8M75.9 19.4v.9M33.9 39.3v1.1l-.4 .2M34.5 39.7l.3-.4v1.3M62.9 40l.6-.1 .1-.5-.7-.1v1.3M63.2 40l.5 .6M64.9 39.4a.58 .58 0 0 0-.8 .5 .58 .58 0 0 0 .8 .5v-.4h-.2M69.4 33.1l.5-1.6 .5 1.6M69.5 32.6h.7M70.9 31.5a.77 .77 0 0 1 .9 .8 .77 .77 0 0 1-.9 .8z"/>
<path d="M72.1 22.2l.6-.1 .1-.5-.7-.1v1.3M72.4 22.2l.4 .6M73.1 31.5l-.5 .1a1.03 1.03 0 0 0 0 1.5l.5-.2 .1-.5-.3-.3h-.3l-.3 .3M73.8 31.7l.6-.2 .2 .5-.9 1.1h.9M73.8 29v1.2l.3 .3h.4l.2-.3v-1.2M74 21.5h-.6l-.1 .6h.6l.1 .6-.2 .1-.5-.1M75.1 21.5l-.3 .1-.2 .2-.1 .7 .3 .3 .4-.1-.1-.6-.3-.1-.3 .2M75.3 30.5h.9M75.3 29.4l.5-.4v1.5M75.4 31.7l.2-.2a.81 .81 0 0 1 .5 .8 .81 .81 0 0 1-.5 .8l-.2-.2-.2-.4zM75.9 21.6l.1-.1a.68 .68 0 0 1 .5 .7 .68 .68 0 0 1-.5 .6l-.3-.5zM76.5 33.1l.5-1.6 .6 1.6"/>
<path d="M76.7 32.6h.7M76.9 22.8h.3v-.3a.54 .54 0 0 1-.2-.7 .54 .54 0 0 1 .7-.2l.2 .6-.3 .3v.3h.3M78.9 31.5v1.6l-.8-1.6v1.6M79.5 31.5h1l-1 1.6h1M85.1 40l.6-.1v-.5l-.6-.1v1.3M85.4 40l.4 .6M87 39.4a.58 .58 0 0 0-.7 .5 .58 .58 0 0 0 .8 .5v-.4h-.3M29.6 42a.56 .56 0 0 0-.8 .5 .56 .56 0 0 0 .8 .5M30.2 42.4l.1-.1 .4 .1-.1 .6h-.4zM31.3 42.4l.5-.1 .1 .8M31.3 42.3v.8M32.5 42.4l.4-.1 .1 .8"/>
<path d="M32.5 42.3v.8M33.3 43.2h1M34.5 40.6h.7M34.6 42l.2-.2a.68 .68 0 0 1 .5 .7 .68 .68 0 0 1-.5 .6l-.3-.5zM35.7 43.1h.7M35.7 42.2l.4-.4v1.3M36.9 42.3l.6 .8M37.5 42.3l-.6 .8M38.1 42l.2-.2a.68 .68 0 0 1 .4 .7 .68 .68 0 0 1-.4 .6l-.3-.5zM39.1 41.8h.8l-.4 .5 .3 .1v.6l-.2 .1-.5-.1M45.1 45.8l1.3 .4-1.3 .4M45.6 47l.3 .2-.1 .4-.6 .1-.1-.5 .2-.2 .8 .1 .2 .1 .1 .4"/>
<path d="M45.9 48.3v.9M62.9 47.7h1M62.9 42.6h1M62.9 45.2h1M63.4 44.7v.9M64.3 46.9l.5 1.3 .4-1.3M64.5 41.8v1.3M64.5 44.4v1.2M65.8 41.8v1.3l-.7-1.3v1.3M65.8 44.4v1.2l-.7-1.2v1.2M66.3 47h-.7v.4l.5 .2 .2 .3-.3 .3-.5-.1M80.4 44.6l.3-.2a.43 .43 0 0 1 .5 .4v.4a.42 .42 0 0 1-.4 .5 .42 .42 0 0 1-.4-.5z"/>
<path d="M81.8 44.4v1l.2 .2h.4l.1-.2v-1M82.9 44.4h.7M83.3 44.4v1.2M83.7 42.6h1M84.1 45h.6v-.5l-.6-.1v1.2M84.1 47.6l.6-.1 .1-.5-.7-.1v1.3M84.2 42.1v1M84.4 47.6l.4 .6M85.1 41.8l.5 1.3 .4-1.3M85.3 44.4v1l.3 .2h.3l.1-.2v-1M85.4 47.5h.4M86 46.9h-.6v1.3h.6"/>
<path d="M86.5 44.4h.7M86.5 47.5h.5M86.8 44.4v1.2M87.1 41.9l-.7 .1v.3l.6 .3 .1 .3-.3 .2-.5-.1M87.1 46.9h-.6v1.3M94.3 54.6a.58 .58 0 0 0-.7 .6 .58 .58 0 0 0 .8 .5v-.5h-.3M95.6 54.5v1.3l-.7-1.3v1.3M96.3 54.5a.64 .64 0 0 1 .7 .7 .64 .64 0 0 1-.7 .6zM100.8 42.6h.9M101.3 42.1v1M103 42.4l-.2 .2h-.4l-.1-.6 .5-.2 .2 .3v.7l-.2 .2-.4 .1M103.4 41.8l.4 1.3 .4-1.3"/>
</g>
<path d="M72.4 25h5.1v2h-5.1zM33.1 45.1h2.5v7.6h-2.5z" fill="none" stroke="#840000" stroke-width=".25"/>
<g fill="none" stroke="#a90000" stroke-width=".21">
<path d="M58.1 39.6h.7M58.1 38.7l.4-.4v1.3M91.4 38.8l-.3 .3 .1 .3 .2 .2 .3-.1 .1-.2v-.2l-.2-.3M91.4 38.8l-.3-.2 .3-.3h.2l.2 .2-.2 .3M91.4 38.8h.2M37.1 49.7h.8l-.4 .5 .3 .1v.6l-.1 .1-.6-.1M37.2 45.9h.7M37.2 45l.3-.4v1.3M37.2 47.3l.5-.1 .2 .3-.8 1h.8M58.1 43.4h.7l-.4 .5 .4 .1v.5l-.2 .1-.5-.1M58.1 41l.5-.2 .2 .4-.7 .9h.7M58.4 45.9l-.3 .9h.8"/>
<path d="M58.7 46.3v.9M91.1 40.8h.8l-.5 1.3M91.7 43.4h-.3l-.2 .3-.1 .7 .3 .2 .4-.1-.1-.6h-.3l-.3 .2M91.8 45.9h-.6l-.1 .6h.6l.1 .6-.2 .1-.5-.1"/>
</g>
<g fill="#009600">
<circle cx="167" cy="145.3" r=".46"/>
<circle cx="137.8" cy="145.3" r=".46"/>
<circle cx="135.9" cy="101.5" r=".46"/>
<circle cx="142.2" cy="86.3" r=".46"/>
<circle cx="144.8" cy="45.1" r=".46"/>
<circle cx="124.5" cy="45.1" r=".46"/>
<circle cx="151.1" cy="26" r=".46"/>
<circle cx="71.2" cy="121.9" r=".46"/>
<circle cx="210.8" cy="24.8" r=".46"/>
<circle cx="247.6" cy="47.6" r=".46"/>
<circle cx="191.7" cy="43.8" r=".46"/>
<circle cx="210.8" cy="43.8" r=".46"/>
<circle cx="175.2" cy="43.8" r=".46"/>
<circle cx="115.6" cy="101.5" r=".46"/>
<circle cx="47.1" cy="105.4" r=".46"/>
<circle cx="87.7" cy="101.5" r=".46"/>
<circle cx="87.7" cy="110.4" r=".46"/>
<circle cx="95.3" cy="47.6" r=".46"/>
</g>
</svg>
